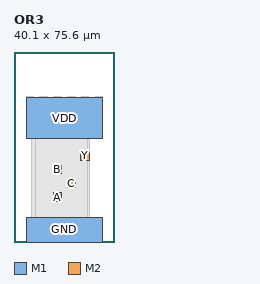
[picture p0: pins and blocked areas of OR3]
MACRO OR3
  CLASS CORE ;
  ORIGIN 0 0 ;
  SIZE 40.100 BY 75.600 ;
  SYMMETRY X Y ;
  SITE TR1um_access_site ;
  PIN VDD
    DIRECTION INOUT ;
    USE POWER ;
    PORT
      LAYER M1 ;
        RECT 5.000 41.000 35.100 57.600 ;
    END
  END VDD
  PIN GND
    DIRECTION INOUT ;
    USE GROUND ;
    PORT
      LAYER M1 ;
        RECT 5.000 0.000 35.100 9.800 ;
    END
  END GND
  PIN A
    DIRECTION INPUT ;
    USE SIGNAL ;
    PORT
      LAYER M2 ;
        RECT 15.600 16.100 19.000 19.500 ;
    END
  END A
  PIN B
    DIRECTION INPUT ;
    USE SIGNAL ;
    PORT
      LAYER M2 ;
        RECT 15.600 27.100 19.000 30.500 ;
    END
  END B
  PIN C
    DIRECTION INPUT ;
    USE SIGNAL ;
    PORT
      LAYER M2 ;
        RECT 21.100 21.600 24.500 25.000 ;
    END
  END C
  PIN Y
    DIRECTION OUTPUT ;
    USE SIGNAL ;
    PORT
      LAYER M2 ;
        RECT 26.600 32.600 30.000 36.000 ;
    END
  END Y
  OBS
    LAYER M1 ;
      RECT 12.600 16.100 19.000 23.900 ;
    LAYER M1 ;
      RECT 21.100 21.600 24.500 29.700 ;
    LAYER M1 ;
      RECT 10.400 27.100 19.000 35.700 ;
    LAYER M1 ;
      RECT 7.100 6.400 25.700 51.200 ;
    LAYER M1 ;
      RECT 13.100 41.000 15.700 51.200 ;
    LAYER M1 ;
      RECT 17.100 41.000 19.700 51.200 ;
    LAYER M1 ;
      RECT 25.100 6.400 30.000 51.200 ;
    LAYER V1 ;
      RECT 4.800 0.000 7.800 2.800 ;
    LAYER V1 ;
      RECT 10.300 0.000 13.300 2.800 ;
    LAYER V1 ;
      RECT 15.800 0.000 18.800 2.800 ;
    LAYER V1 ;
      RECT 21.300 0.000 24.300 2.800 ;
    LAYER V1 ;
      RECT 26.800 0.000 29.800 2.800 ;
    LAYER V1 ;
      RECT 32.300 0.000 35.300 2.800 ;
    LAYER V1 ;
      RECT 16.600 17.100 18.000 18.500 ;
    LAYER V1 ;
      RECT 16.600 28.100 18.000 29.500 ;
    LAYER V1 ;
      RECT 27.600 33.600 29.000 35.000 ;
    LAYER V1 ;
      RECT 8.700 4.000 29.200 53.600 ;
    LAYER V1 ;
      RECT 4.800 54.800 7.800 57.800 ;
    LAYER V1 ;
      RECT 10.300 54.800 13.300 57.800 ;
    LAYER V1 ;
      RECT 15.800 54.800 18.800 57.800 ;
    LAYER V1 ;
      RECT 21.300 54.800 24.300 57.800 ;
    LAYER V1 ;
      RECT 26.800 54.800 29.800 57.800 ;
    LAYER V1 ;
      RECT 32.300 54.800 35.300 57.800 ;
  END
END OR3
